! (c) 2009  Infineon Technologies AG, Munich
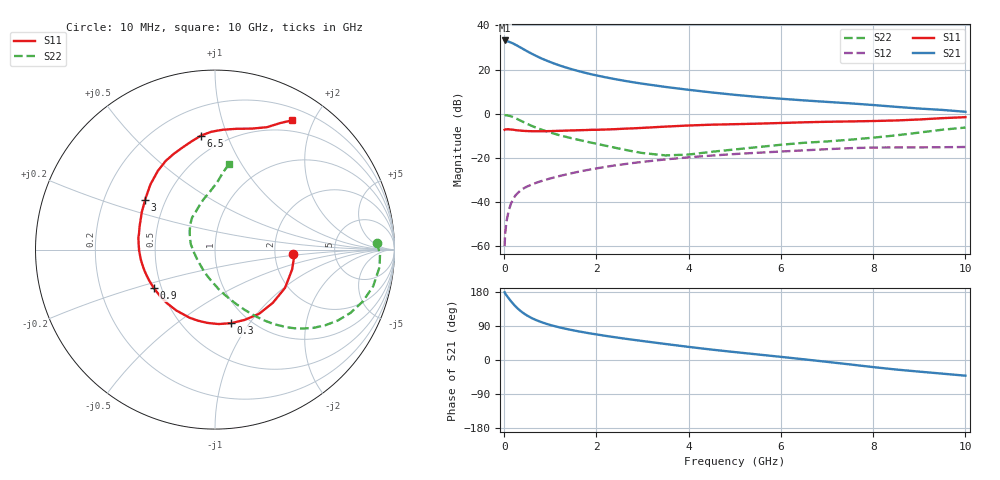
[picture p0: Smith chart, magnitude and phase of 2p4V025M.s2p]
! Infineon Technologies  Discrete & RF Semiconductors
! BFP420
! VCE =  4.0 V,  IC =  25 mA
! Common Emitter S-Parameters:  Nov 2009
# GHz  S  MA  R  50
!  f  S11  S21  S12  S22
! GHz  MAG  ANG  MAG  ANG  MAG  ANG  MAG  ANG
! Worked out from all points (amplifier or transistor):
!   46 points, 10 MHz to 10 GHz, reference 50 ohm
!   highest |S21| = 33.2 dB at 10 MHz (marker M1)
!   |S21| within 3 dB of that: start of sweep to 338.8 MHz
!   unconditionally stable (mu >= 1): start of sweep to 21.28 MHz; 1.696 GHz to end of sweep
!   at 300 MHz: K = 0.40, MSG = 33.2 dB, |S12| = -35.8 dB
!   at 1.7 GHz: K = 1.00, MAG = 22.2 dB, |S12| = -25.9 dB
!   at 10 GHz: K = 1.07, MAG = 6.4 dB, |S12| = -15.1 dB
!   lowest NFmin = 1.38 dB at 900 MHz
!   S11 on the Smith chart (normalised r, x): 10 MHz: 2.52, -0.15; 300 MHz: 0.83, -0.82; 900 MHz: 0.46, -0.23; 3 GHz: 0.38, +0.28; 6.5 GHz: 0.38, +0.81; 10 GHz: 0.35, +1.70
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0.01  0.4342 -3.1  45.73 178.7  0.001 61.5  0.9027 2.4
0.02  0.4422 -5.5  44.45 175.9  0.0018 53.4  0.9197 -1.8
0.05  0.4438 -14.3  43.86 170.8  0.0036 68.3  0.922 -6.0
0.1  0.4447 -28.7  42.76 162.6  0.0065 71.6  0.9049 -13.0
0.15  0.4379 -42.5  40.93 154.8  0.0093 70.3  0.8731 -19.3
0.2  0.4341 -55.3  38.8 147.7  0.012 67.9  0.8334 -25.0
0.25  0.4252 -67.0  36.37 141.0  0.0143 65.3  0.7903 -30.0
0.3  0.4198 -77.5  34.13 135.2  0.0162 63.3  0.7456 -34.4
0.45  0.4073 -103.4  27.79 121.0  0.0212 59.1  0.6245 -44.6
0.6  0.4018 -122.3  22.83 110.5  0.025 57.0  0.5301 -51.6
0.7  0.4012 -132.2  20.24 105.0  0.0274 56.5  0.4806 -55.2
0.9  0.4022 -147.6  16.31 96.1  0.0319 56.0  0.4051 -61.0
1.2  0.4106 -164.0  12.44 86.1  0.0388 55.7  0.3266 -68.6
1.7  0.4254 177.0  8.769 73.7  0.0506 54.3  0.2443 -80.1
2.2  0.4395 162.9  6.686 63.7  0.0627 51.5  0.1887 -92.4
3  0.4786 144.5  4.791 50.1  0.0813 45.4  0.1289 -121.8
3.5  0.5113 134.7  4.047 42.2  0.0923 41.0  0.1138 -148.0
5.5  0.5965 107.8  2.407 14.6  0.1308 22.9  0.1755 143.5
6.5  0.6401 97.0  2.007 1.8  0.1482 13.8  0.2197 125.5
7  0.6572 91.7  1.855 -4.9  0.1574 9.0  0.236 117.2
8.5  0.7045 73.1  1.432 -25.2  0.1724 -7.9  0.3238 95.0
10  0.8366 59.3  1.107 -41.4  0.1765 -19.2  0.4862 80.5
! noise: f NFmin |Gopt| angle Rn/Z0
0.9  1.38  0.22  -154  0.13
1.8  1.65  0.29  -143  0.13
2.4  1.81  0.26  -138  0.17
3  1.83  0.34  -129  0.18
4  1.97  0.45  -112  0.27
5  2.4  0.49  -95  0.44
6  2.85  0.54  -84  0.65
